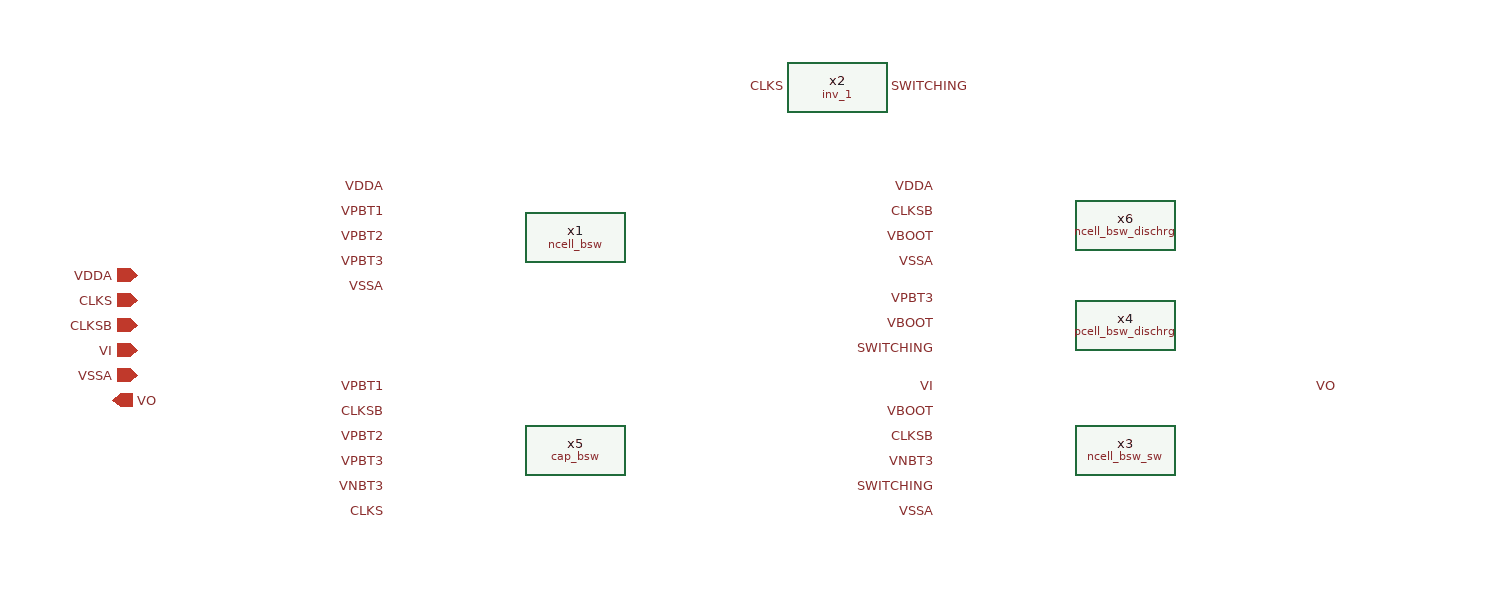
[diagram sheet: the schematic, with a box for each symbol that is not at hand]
v {xschem version=3.4.5 file_version=1.2
}
G {}
K {}
V {}
S {}
E {}
C {devices/title.sym} 160 -30 0 0 {name=l5 author="Yohanes Stefanus"}
C {devices/lab_pin.sym} 700 -550 0 0 {name=p20 sig_type=std_logic lab=CLKS}
C {devices/ipin.sym} 180 -400 0 0 {name=p26 lab=VDDA
}
C {sky130_stdcells/inv_1.sym} 740 -550 0 0 {name=x2 VGND=VNBT3 VNB=VSSA VPB=VDDA VPWR=VDDA prefix=sky130_fd_sc_hd__ }
C {devices/lab_pin.sym} 780 -550 0 1 {name=p4 sig_type=std_logic lab=SWITCHING
}
C {devices/ipin.sym} 180 -380 0 0 {name=p1 lab=CLKS
}
C {devices/ipin.sym} 180 -360 0 0 {name=p2 lab=CLKSB
}
C {devices/ipin.sym} 180 -340 0 0 {name=p6 lab=VI}
C {devices/ipin.sym} 180 -320 0 0 {name=p8 lab=VSSA
}
C {devices/opin.sym} 160 -300 0 0 {name=p9 lab=VO}
C {ncell_bsw_sw.sym} 970 -260 0 0 {name=x3}
C {pcell_bsw_dischrg.sym} 970 -360 0 0 {name=x4}
C {cap_bsw.sym} 530 -260 0 0 {name=x5}
C {ncell_bsw_dischrg.sym} 970 -440 0 0 {name=x6}
C {devices/lab_pin.sym} 380 -390 0 0 {name=p27 sig_type=std_logic lab=VSSA}
C {devices/lab_pin.sym} 820 -210 0 0 {name=p28 sig_type=std_logic lab=VSSA}
C {devices/lab_pin.sym} 820 -410 0 0 {name=p29 sig_type=std_logic lab=VSSA}
C {devices/lab_pin.sym} 380 -450 0 0 {name=p30 sig_type=std_logic lab=VPBT1}
C {devices/lab_pin.sym} 380 -310 0 0 {name=p32 sig_type=std_logic lab=VPBT1}
C {devices/lab_pin.sym} 380 -410 0 0 {name=p37 sig_type=std_logic lab=VPBT3}
C {devices/lab_pin.sym} 380 -250 0 0 {name=p38 sig_type=std_logic lab=VPBT3}
C {devices/lab_pin.sym} 380 -230 0 0 {name=p40 sig_type=std_logic lab=VNBT3}
C {devices/lab_pin.sym} 380 -210 0 0 {name=p41 sig_type=std_logic lab=CLKS}
C {devices/lab_pin.sym} 380 -470 0 0 {name=p42 sig_type=std_logic lab=VDDA}
C {devices/lab_pin.sym} 820 -470 0 0 {name=p43 sig_type=std_logic lab=VDDA}
C {devices/lab_pin.sym} 820 -250 0 0 {name=p44 sig_type=std_logic lab=VNBT3}
C {devices/lab_pin.sym} 820 -380 0 0 {name=p45 sig_type=std_logic lab=VPBT3}
C {devices/lab_pin.sym} 820 -430 0 0 {name=p46 sig_type=std_logic lab=VBOOT}
C {devices/lab_pin.sym} 820 -290 0 0 {name=p47 sig_type=std_logic lab=VBOOT}
C {devices/lab_pin.sym} 820 -230 0 0 {name=p48 sig_type=std_logic lab=SWITCHING}
C {devices/lab_pin.sym} 820 -340 0 0 {name=p49 sig_type=std_logic lab=SWITCHING}
C {devices/lab_pin.sym} 820 -360 0 0 {name=p50 sig_type=std_logic lab=VBOOT}
C {devices/lab_pin.sym} 820 -310 2 1 {name=p51 sig_type=std_logic lab=VI}
C {devices/lab_pin.sym} 1120 -310 0 1 {name=p52 sig_type=std_logic lab=VO}
C {devices/lab_pin.sym} 820 -450 0 0 {name=p53 sig_type=std_logic lab=CLKSB}
C {devices/lab_pin.sym} 380 -270 0 0 {name=p54 sig_type=std_logic lab=VPBT2}
C {devices/lab_pin.sym} 380 -290 0 0 {name=p56 sig_type=std_logic lab=CLKSB}
C {devices/lab_pin.sym} 380 -430 0 0 {name=p33 sig_type=std_logic lab=VPBT2}
C {devices/lab_pin.sym} 820 -270 0 0 {name=p3 sig_type=std_logic lab=CLKSB}
C {ncell_bsw.sym} 530 -430 0 0 {name=x1}
